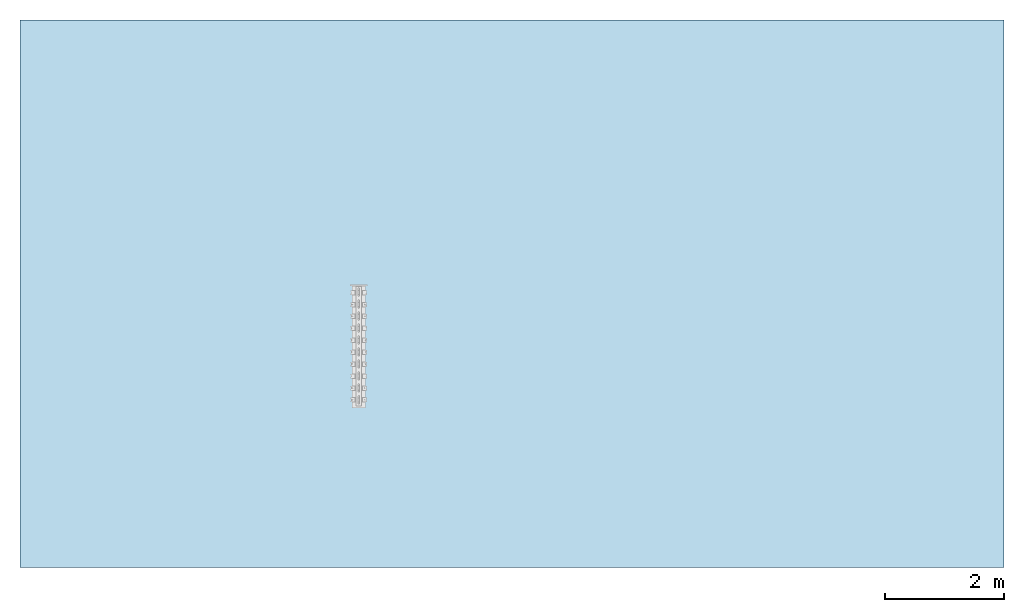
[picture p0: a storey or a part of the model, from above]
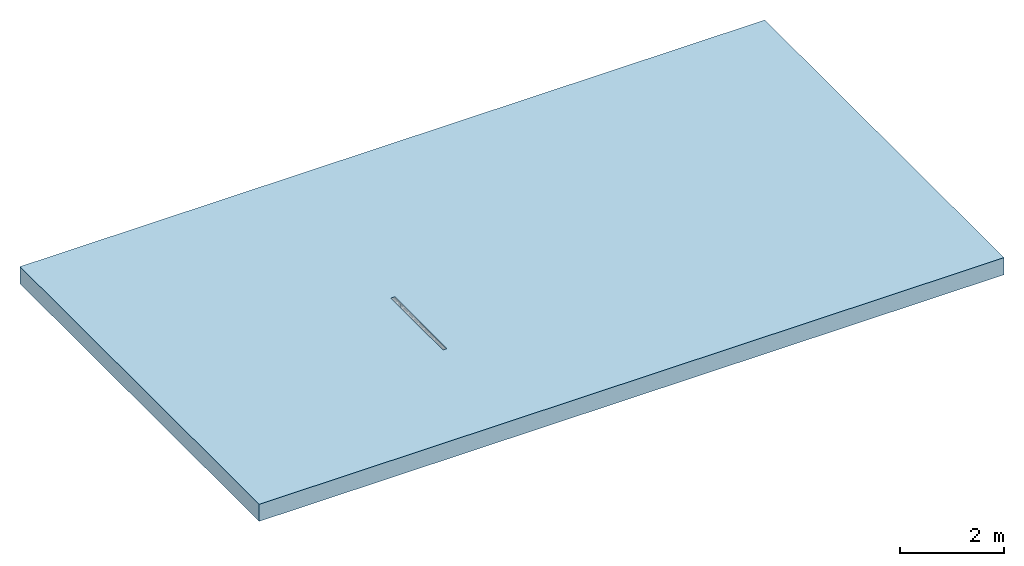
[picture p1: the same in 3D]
Properties of the parts of a building model (IFC2X3)

# File
Description: ViewDefinition [CoordinationView]
File name: 32802 - Q-Flow Edge - G.S.ifc
Time: 2013-09-04T16:51:20
Written by: Autodesk Revit 2013
Made in: 20120221_2030(x64)

# IfcProject, Project Number
LongName: Project Name; Phase: Project Status

# IfcSite, Default
RefLatitude: 42, 21, 30, 344238; RefLongitude: -71, -3, -35, -194702; RefElevation: 0 mm

# IfcBuilding
Pset_BuildingCommon - NumberOfStoreys: 1
Other - Client Name: Owner; Project Number: Project Number; Project Address: ## Street City, State Zip; Project Issue Date: Issue Date; Project Status: Project Status; Project Name: Project Name

# IfcBuildingStorey, Level 1
LongName: Level 1; Elevation: 0 mm
Constraints - Elevation Base: 0; Elevation: 0 mm
Graphics - Color: 0; Line Weight: 1; Symbol at End 1 Default: no; Line Pattern: Center; Symbol at End 2 Default: yes; Symbol: M_Level Head - Circle: M_Level Head - Circle
Identity Data - Structural: no; Building Story: yes; Name: Level 1
Dimensions - Computation Height: 0 mm

# IfcFlowTerminal: 32802 - Q-Flow Edge - G.S, Qmax 225:32802 - Q-Flow Edge - G.S:32802 - Q-Flow Edge - G.S:351197
In: Level 1
Phasing - Phase Created: New Construction
Construction - 42221_225 End Cap (at Female end): no; 42221_225 End Cap (at Male end): no; 32995_150-225 Step Connector: no; V_Coarse_E5: no; E5-QSlot-GalvSteel: no; E1-QFlow-DuctileIron: no; E4-QGuard-GalvSteel: no; V_CoarseE1: yes; E2-QGuard-DuctileIron: no; E3-QFlow-GalvSteel: yes
Identity Data - Mark: 62; Price: POA - contact ACO; Type Comments: ACO Qmax 225 channel assembly complete with ACO Q-Flow galvanised steel edge rail; e-mail Technical: technical@aco.co.uk; Installation Guidelines: http://www.aco.co.uk/download.php?id=220; Telephone: +44 (0)1462 816666; URL: www.aco.co.uk; OmniClass Title: Rainwater Removal; Address: ACO Business Park, Hitchin Road, Shefford, Bedfordshire, United Kingdom SG17 5TE; Cost: 0; Assembly Code: D2040; Product Brochure: http://www.aco.co.uk/download.php?id=220; Assembly Description: Rain Water Drainage; OmniClass Number: 23.70.50.24; Product Page URL: http://www.aco.co.uk/product_detail.php?id=79; Product Code: 32802; Maintenance Guidelines: http://www.aco.co.uk/download.php?id=220; e-mail Sales: customersupport@aco.co.uk; Manufacturer: ACO Technologies plc - ACO Water Management Division; Model Description: High capacity slot drainage channel system; Fax: +44 (0)1462 815895; Model: ACO Qmax 225
Constraints - Moves With Nearby Elements: no; Level: Level: Level 1
Data - Invert Depth: 425mm; Installation - Reinforcement Details: Refer to brochure; Installation - Concrete Grade: Refer to brochure; Hydraulic Performance: http://www.aco.co.uk/download.php?id=220; Channel C.S.A: 39761mm²; Concrete Surround Volume - Load Class F 900: 0.345 m³/m; Concrete Surround Volume - Load Class A 15 - E 600: 0.255 m³/m; Drainage Slot Intake Area: 18106mm²/m; Product Dimensions: 2000mm x 290mm x 480mm (LxWxH); Product Weight: 17.8 kg; Drainage Slot Width: 26mm; ACO Hydraulic Design Software: http://www.acodesign.co.uk; Product Standard: BS EN 1433:2002 CE marked; Load Class: A 15 - F 900
General - SerialNumber: 0; TagNumber: 0
Model Properties - Multi-functional End Cap - Weight: 1.4 kg; Multi-functional End Cap - Dimensions: Ø290mm x 240mm (ØxL); Multi-functional End Cap - Channel Recycled Material Content: Variable %; 150-225 Step Connector - Recyclable: Fully recyclable; 150-225 Step Connector - Model Description: High capacity slot drainage channel system; 150-225 Step Connector - Material: High Density Polyethylene; 150-225 Step Connector - Weight: 0.4 kg; Multi-functional End Cap - Seal Material: Chloroprene; 150-225 Step Connector - Colour: Black Medium Density Polyethylene; Multi-functional End Cap - Seal Recycled Material Content: 0%; Multi-functional End Cap - Seal Colour: Black; Multi-functional End Cap - Product Code: 42221; Multi-functional End Cap - Channel Colour: Black Medium Density Polyethylene; 150-225 Step Connector - Recycled Material Content: 0%; Multi-functional End Cap - Channel Recyclable: Fully recyclable; Multi-functional End Cap - Model Description: High capacity slot drainage channel system; 150-225 Step Connector - Product Code: 32995; 150-225 Step Connector - Dimensions: Ø310mm x 25mm (ØxL); Multi-functional End Cap - Seal Recyclable: Fully recyclable; Multi-functional End Cap - Channel Material: Medium Density Polyethylene
Dimensions - Width Overall: 290 mm; Floor Opening Width: 90 mm; Length: 2000 mm; BoreCentre: 311.5 mm; Depth Overall: 480 mm
Green Building Properties - Channel Recycled Material Content: Variable %; Edge Rail Recyclable: Fully recyclable; Seal Recycled Material Content: 0%; Edge Rail Recycled Material Content: Between 40% - 90%; Channel Recyclable: Fully recyclable; Seal Recyclable: Fully recyclable
Materials and Finishes - Edge Rail Finish: Galvanised; Seal Colour: Black; Seal Material: Chloroprene; Edge Rail Material: Steel; Channel Material: Medium Density Polyethylene; Channel Colour: Black; Edge Rail Colour: Silver Silver
Other - Created by: www.aco.co.uk; Revision: 1

# IfcOpeningElement: Opening
In: Level 1
Constraints - Height Offset From Level: 0 mm; Related to Mass: no; Level: Level: Level 1; Room Bounding: yes
Structural - Structural: no; Enable Analytical Model: no
Phasing - Phase Created: New Construction
Dimensions - Perimeter: 51360 mm; Volume: 60331000000 mm3; Thickness: 400 mm; Area: 151290000 mm2
Construction - Function: 0; Default Thickness: 400 mm
Analytical Properties - Roughness: 1; Absorptance: 0.1
Graphics - Coarse Scale Fill Color: 0
Materials and Finishes - Structural Material: Plant

# IfcSlab: Floor:Generic Floor - 400mm, Floor:Generic Floor - 400mm:193825
In: Level 1
PredefinedType: FLOOR; Material: Plant 400 mm
Constraints - Height Offset From Level: 0 mm; Related to Mass: no; Level: Level: Level 1; Room Bounding: yes
Structural - Structural: no; Enable Analytical Model: no
Phasing - Phase Created: New Construction
Dimensions - Perimeter: 51360 mm; Volume: 60331000000 mm3; Thickness: 400 mm; Area: 151290000 mm2
Pset_SlabCommon - Reference: Generic Floor - 400mm; IsExternal: no; LoadBearing: yes
Construction - Function: 0; Default Thickness: 400 mm
Analytical Properties - Roughness: 1; Absorptance: 0.1
Graphics - Coarse Scale Fill Color: 0
Materials and Finishes - Structural Material: Plant
